VERSION 5.8 ;
BUSBITCHARS "[]" ;
DIVIDERCHAR "/" ;
UNITS
    DATABASE MICRONS 1000 ;
END UNITS

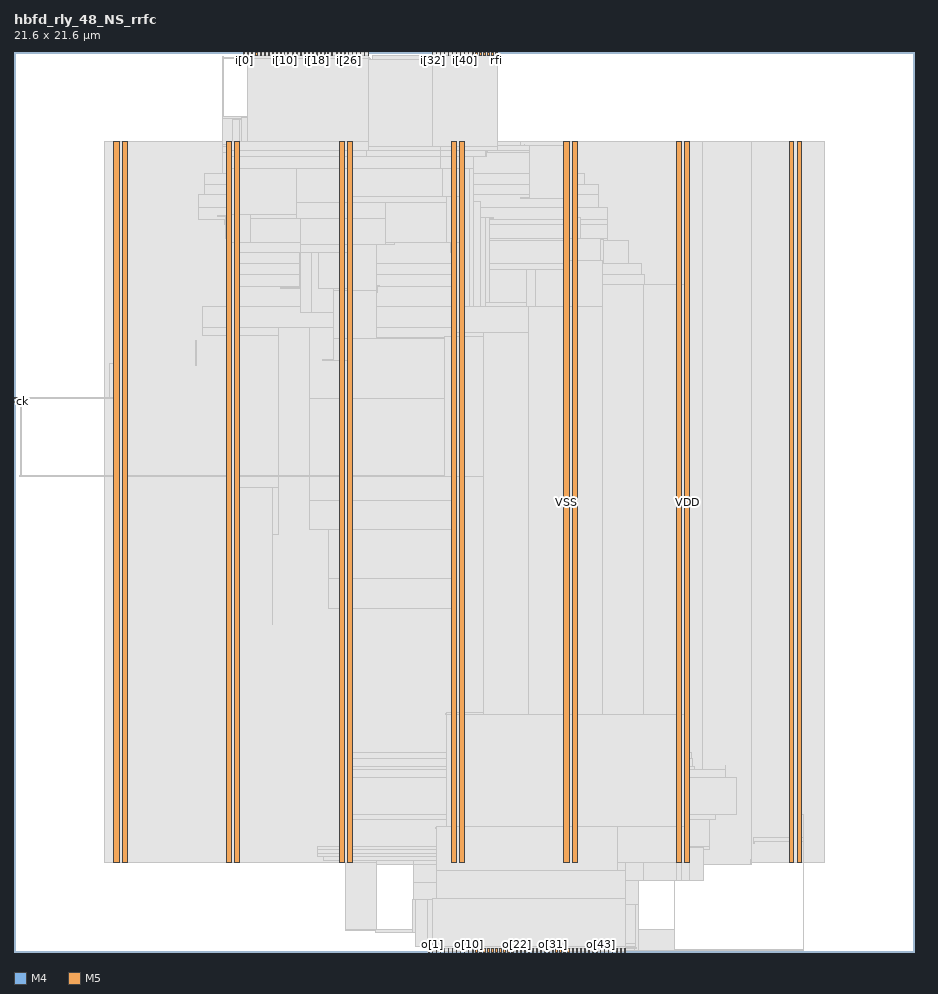
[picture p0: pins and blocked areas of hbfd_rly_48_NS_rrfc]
MACRO hbfd_rly_48_NS_rrfc
  FOREIGN hbfd_rly_48_NS_rrfc 0 0 ;
  CLASS BLOCK ;
  SIZE 21.6 BY 21.6 ;
  PIN ck
    DIRECTION INPUT ;
    USE SIGNAL ;
    PORT
      LAYER M4 ;
        RECT  0 13.2 0.084 13.224 ;
    END
  END ck
  PIN i[0]
    DIRECTION INPUT ;
    USE SIGNAL ;
    PORT
      LAYER M5 ;
        RECT  5.52 21.516 5.544 21.6 ;
    END
  END i[0]
  PIN i[10]
    DIRECTION INPUT ;
    USE SIGNAL ;
    PORT
      LAYER M5 ;
        RECT  6.48 21.516 6.504 21.6 ;
    END
  END i[10]
  PIN i[11]
    DIRECTION INPUT ;
    USE SIGNAL ;
    PORT
      LAYER M5 ;
        RECT  6.576 21.516 6.6 21.6 ;
    END
  END i[11]
  PIN i[12]
    DIRECTION INPUT ;
    USE SIGNAL ;
    PORT
      LAYER M5 ;
        RECT  6.672 21.516 6.696 21.6 ;
    END
  END i[12]
  PIN i[13]
    DIRECTION INPUT ;
    USE SIGNAL ;
    PORT
      LAYER M5 ;
        RECT  6.768 21.516 6.792 21.6 ;
    END
  END i[13]
  PIN i[14]
    DIRECTION INPUT ;
    USE SIGNAL ;
    PORT
      LAYER M5 ;
        RECT  6.864 21.516 6.888 21.6 ;
    END
  END i[14]
  PIN i[15]
    DIRECTION INPUT ;
    USE SIGNAL ;
    PORT
      LAYER M5 ;
        RECT  6.96 21.516 6.984 21.6 ;
    END
  END i[15]
  PIN i[16]
    DIRECTION INPUT ;
    USE SIGNAL ;
    PORT
      LAYER M5 ;
        RECT  7.056 21.516 7.08 21.6 ;
    END
  END i[16]
  PIN i[17]
    DIRECTION INPUT ;
    USE SIGNAL ;
    PORT
      LAYER M5 ;
        RECT  7.152 21.516 7.176 21.6 ;
    END
  END i[17]
  PIN i[18]
    DIRECTION INPUT ;
    USE SIGNAL ;
    PORT
      LAYER M5 ;
        RECT  7.248 21.516 7.272 21.6 ;
    END
  END i[18]
  PIN i[19]
    DIRECTION INPUT ;
    USE SIGNAL ;
    PORT
      LAYER M5 ;
        RECT  7.344 21.516 7.368 21.6 ;
    END
  END i[19]
  PIN i[1]
    DIRECTION INPUT ;
    USE SIGNAL ;
    PORT
      LAYER M5 ;
        RECT  5.616 21.516 5.64 21.6 ;
    END
  END i[1]
  PIN i[20]
    DIRECTION INPUT ;
    USE SIGNAL ;
    PORT
      LAYER M5 ;
        RECT  7.44 21.516 7.464 21.6 ;
    END
  END i[20]
  PIN i[21]
    DIRECTION INPUT ;
    USE SIGNAL ;
    PORT
      LAYER M5 ;
        RECT  7.536 21.516 7.56 21.6 ;
    END
  END i[21]
  PIN i[22]
    DIRECTION INPUT ;
    USE SIGNAL ;
    PORT
      LAYER M5 ;
        RECT  7.632 21.516 7.656 21.6 ;
    END
  END i[22]
  PIN i[23]
    DIRECTION INPUT ;
    USE SIGNAL ;
    PORT
      LAYER M5 ;
        RECT  7.728 21.516 7.752 21.6 ;
    END
  END i[23]
  PIN i[24]
    DIRECTION INPUT ;
    USE SIGNAL ;
    PORT
      LAYER M5 ;
        RECT  7.824 21.516 7.848 21.6 ;
    END
  END i[24]
  PIN i[25]
    DIRECTION INPUT ;
    USE SIGNAL ;
    PORT
      LAYER M5 ;
        RECT  7.92 21.516 7.944 21.6 ;
    END
  END i[25]
  PIN i[26]
    DIRECTION INPUT ;
    USE SIGNAL ;
    PORT
      LAYER M5 ;
        RECT  8.016 21.516 8.04 21.6 ;
    END
  END i[26]
  PIN i[27]
    DIRECTION INPUT ;
    USE SIGNAL ;
    PORT
      LAYER M5 ;
        RECT  8.112 21.516 8.136 21.6 ;
    END
  END i[27]
  PIN i[28]
    DIRECTION INPUT ;
    USE SIGNAL ;
    PORT
      LAYER M5 ;
        RECT  8.208 21.516 8.232 21.6 ;
    END
  END i[28]
  PIN i[29]
    DIRECTION INPUT ;
    USE SIGNAL ;
    PORT
      LAYER M5 ;
        RECT  8.304 21.516 8.328 21.6 ;
    END
  END i[29]
  PIN i[2]
    DIRECTION INPUT ;
    USE SIGNAL ;
    PORT
      LAYER M5 ;
        RECT  5.712 21.516 5.736 21.6 ;
    END
  END i[2]
  PIN i[30]
    DIRECTION INPUT ;
    USE SIGNAL ;
    PORT
      LAYER M5 ;
        RECT  8.4 21.516 8.424 21.6 ;
    END
  END i[30]
  PIN i[31]
    DIRECTION INPUT ;
    USE SIGNAL ;
    PORT
      LAYER M5 ;
        RECT  8.496 21.516 8.52 21.6 ;
    END
  END i[31]
  PIN i[32]
    DIRECTION INPUT ;
    USE SIGNAL ;
    PORT
      LAYER M5 ;
        RECT  10.032 21.516 10.056 21.6 ;
    END
  END i[32]
  PIN i[33]
    DIRECTION INPUT ;
    USE SIGNAL ;
    PORT
      LAYER M5 ;
        RECT  10.128 21.516 10.152 21.6 ;
    END
  END i[33]
  PIN i[34]
    DIRECTION INPUT ;
    USE SIGNAL ;
    PORT
      LAYER M5 ;
        RECT  10.224 21.516 10.248 21.6 ;
    END
  END i[34]
  PIN i[35]
    DIRECTION INPUT ;
    USE SIGNAL ;
    PORT
      LAYER M5 ;
        RECT  10.32 21.516 10.344 21.6 ;
    END
  END i[35]
  PIN i[36]
    DIRECTION INPUT ;
    USE SIGNAL ;
    PORT
      LAYER M5 ;
        RECT  10.416 21.516 10.44 21.6 ;
    END
  END i[36]
  PIN i[37]
    DIRECTION INPUT ;
    USE SIGNAL ;
    PORT
      LAYER M5 ;
        RECT  10.512 21.516 10.536 21.6 ;
    END
  END i[37]
  PIN i[38]
    DIRECTION INPUT ;
    USE SIGNAL ;
    PORT
      LAYER M5 ;
        RECT  10.608 21.516 10.632 21.6 ;
    END
  END i[38]
  PIN i[39]
    DIRECTION INPUT ;
    USE SIGNAL ;
    PORT
      LAYER M5 ;
        RECT  10.704 21.516 10.728 21.6 ;
    END
  END i[39]
  PIN i[3]
    DIRECTION INPUT ;
    USE SIGNAL ;
    PORT
      LAYER M5 ;
        RECT  5.808 21.516 5.832 21.6 ;
    END
  END i[3]
  PIN i[40]
    DIRECTION INPUT ;
    USE SIGNAL ;
    PORT
      LAYER M5 ;
        RECT  10.8 21.516 10.824 21.6 ;
    END
  END i[40]
  PIN i[41]
    DIRECTION INPUT ;
    USE SIGNAL ;
    PORT
      LAYER M5 ;
        RECT  10.896 21.516 10.92 21.6 ;
    END
  END i[41]
  PIN i[42]
    DIRECTION INPUT ;
    USE SIGNAL ;
    PORT
      LAYER M5 ;
        RECT  10.992 21.516 11.016 21.6 ;
    END
  END i[42]
  PIN i[43]
    DIRECTION INPUT ;
    USE SIGNAL ;
    PORT
      LAYER M5 ;
        RECT  11.088 21.516 11.112 21.6 ;
    END
  END i[43]
  PIN i[44]
    DIRECTION INPUT ;
    USE SIGNAL ;
    PORT
      LAYER M5 ;
        RECT  11.184 21.516 11.208 21.6 ;
    END
  END i[44]
  PIN i[45]
    DIRECTION INPUT ;
    USE SIGNAL ;
    PORT
      LAYER M5 ;
        RECT  11.28 21.516 11.304 21.6 ;
    END
  END i[45]
  PIN i[46]
    DIRECTION INPUT ;
    USE SIGNAL ;
    PORT
      LAYER M5 ;
        RECT  11.376 21.516 11.4 21.6 ;
    END
  END i[46]
  PIN i[47]
    DIRECTION INPUT ;
    USE SIGNAL ;
    PORT
      LAYER M5 ;
        RECT  11.472 21.516 11.496 21.6 ;
    END
  END i[47]
  PIN i[4]
    DIRECTION INPUT ;
    USE SIGNAL ;
    PORT
      LAYER M5 ;
        RECT  5.904 21.516 5.928 21.6 ;
    END
  END i[4]
  PIN i[5]
    DIRECTION INPUT ;
    USE SIGNAL ;
    PORT
      LAYER M5 ;
        RECT  6 21.516 6.024 21.6 ;
    END
  END i[5]
  PIN i[6]
    DIRECTION INPUT ;
    USE SIGNAL ;
    PORT
      LAYER M5 ;
        RECT  6.096 21.516 6.12 21.6 ;
    END
  END i[6]
  PIN i[7]
    DIRECTION INPUT ;
    USE SIGNAL ;
    PORT
      LAYER M5 ;
        RECT  6.192 21.516 6.216 21.6 ;
    END
  END i[7]
  PIN i[8]
    DIRECTION INPUT ;
    USE SIGNAL ;
    PORT
      LAYER M5 ;
        RECT  6.288 21.516 6.312 21.6 ;
    END
  END i[8]
  PIN i[9]
    DIRECTION INPUT ;
    USE SIGNAL ;
    PORT
      LAYER M5 ;
        RECT  6.384 21.516 6.408 21.6 ;
    END
  END i[9]
  PIN o[0]
    DIRECTION OUTPUT ;
    USE SIGNAL ;
    PORT
      LAYER M5 ;
        RECT  9.936 0 9.96 0.084 ;
    END
  END o[0]
  PIN o[10]
    DIRECTION OUTPUT ;
    USE SIGNAL ;
    PORT
      LAYER M5 ;
        RECT  10.896 0 10.92 0.084 ;
    END
  END o[10]
  PIN o[11]
    DIRECTION OUTPUT ;
    USE SIGNAL ;
    PORT
      LAYER M5 ;
        RECT  10.992 0 11.016 0.084 ;
    END
  END o[11]
  PIN o[12]
    DIRECTION OUTPUT ;
    USE SIGNAL ;
    PORT
      LAYER M5 ;
        RECT  11.088 0 11.112 0.084 ;
    END
  END o[12]
  PIN o[13]
    DIRECTION OUTPUT ;
    USE SIGNAL ;
    PORT
      LAYER M5 ;
        RECT  11.184 0 11.208 0.084 ;
    END
  END o[13]
  PIN o[14]
    DIRECTION OUTPUT ;
    USE SIGNAL ;
    PORT
      LAYER M5 ;
        RECT  11.28 0 11.304 0.084 ;
    END
  END o[14]
  PIN o[15]
    DIRECTION OUTPUT ;
    USE SIGNAL ;
    PORT
      LAYER M5 ;
        RECT  11.376 0 11.4 0.084 ;
    END
  END o[15]
  PIN o[16]
    DIRECTION OUTPUT ;
    USE SIGNAL ;
    PORT
      LAYER M5 ;
        RECT  11.472 0 11.496 0.084 ;
    END
  END o[16]
  PIN o[17]
    DIRECTION OUTPUT ;
    USE SIGNAL ;
    PORT
      LAYER M5 ;
        RECT  11.568 0 11.592 0.084 ;
    END
  END o[17]
  PIN o[18]
    DIRECTION OUTPUT ;
    USE SIGNAL ;
    PORT
      LAYER M5 ;
        RECT  11.664 0 11.688 0.084 ;
    END
  END o[18]
  PIN o[19]
    DIRECTION OUTPUT ;
    USE SIGNAL ;
    PORT
      LAYER M5 ;
        RECT  11.76 0 11.784 0.084 ;
    END
  END o[19]
  PIN o[1]
    DIRECTION OUTPUT ;
    USE SIGNAL ;
    PORT
      LAYER M5 ;
        RECT  10.032 0 10.056 0.084 ;
    END
  END o[1]
  PIN o[20]
    DIRECTION OUTPUT ;
    USE SIGNAL ;
    PORT
      LAYER M5 ;
        RECT  11.856 0 11.88 0.084 ;
    END
  END o[20]
  PIN o[21]
    DIRECTION OUTPUT ;
    USE SIGNAL ;
    PORT
      LAYER M5 ;
        RECT  11.952 0 11.976 0.084 ;
    END
  END o[21]
  PIN o[22]
    DIRECTION OUTPUT ;
    USE SIGNAL ;
    PORT
      LAYER M5 ;
        RECT  12.048 0 12.072 0.084 ;
    END
  END o[22]
  PIN o[23]
    DIRECTION OUTPUT ;
    USE SIGNAL ;
    PORT
      LAYER M5 ;
        RECT  12.144 0 12.168 0.084 ;
    END
  END o[23]
  PIN o[24]
    DIRECTION OUTPUT ;
    USE SIGNAL ;
    PORT
      LAYER M5 ;
        RECT  12.24 0 12.264 0.084 ;
    END
  END o[24]
  PIN o[25]
    DIRECTION OUTPUT ;
    USE SIGNAL ;
    PORT
      LAYER M5 ;
        RECT  12.336 0 12.36 0.084 ;
    END
  END o[25]
  PIN o[26]
    DIRECTION OUTPUT ;
    USE SIGNAL ;
    PORT
      LAYER M5 ;
        RECT  12.432 0 12.456 0.084 ;
    END
  END o[26]
  PIN o[27]
    DIRECTION OUTPUT ;
    USE SIGNAL ;
    PORT
      LAYER M5 ;
        RECT  12.528 0 12.552 0.084 ;
    END
  END o[27]
  PIN o[28]
    DIRECTION OUTPUT ;
    USE SIGNAL ;
    PORT
      LAYER M5 ;
        RECT  12.624 0 12.648 0.084 ;
    END
  END o[28]
  PIN o[29]
    DIRECTION OUTPUT ;
    USE SIGNAL ;
    PORT
      LAYER M5 ;
        RECT  12.72 0 12.744 0.084 ;
    END
  END o[29]
  PIN o[2]
    DIRECTION OUTPUT ;
    USE SIGNAL ;
    PORT
      LAYER M5 ;
        RECT  10.128 0 10.152 0.084 ;
    END
  END o[2]
  PIN o[30]
    DIRECTION OUTPUT ;
    USE SIGNAL ;
    PORT
      LAYER M5 ;
        RECT  12.816 0 12.84 0.084 ;
    END
  END o[30]
  PIN o[31]
    DIRECTION OUTPUT ;
    USE SIGNAL ;
    PORT
      LAYER M5 ;
        RECT  12.912 0 12.936 0.084 ;
    END
  END o[31]
  PIN o[32]
    DIRECTION OUTPUT ;
    USE SIGNAL ;
    PORT
      LAYER M5 ;
        RECT  13.008 0 13.032 0.084 ;
    END
  END o[32]
  PIN o[33]
    DIRECTION OUTPUT ;
    USE SIGNAL ;
    PORT
      LAYER M5 ;
        RECT  13.104 0 13.128 0.084 ;
    END
  END o[33]
  PIN o[34]
    DIRECTION OUTPUT ;
    USE SIGNAL ;
    PORT
      LAYER M5 ;
        RECT  13.2 0 13.224 0.084 ;
    END
  END o[34]
  PIN o[35]
    DIRECTION OUTPUT ;
    USE SIGNAL ;
    PORT
      LAYER M5 ;
        RECT  13.296 0 13.32 0.084 ;
    END
  END o[35]
  PIN o[36]
    DIRECTION OUTPUT ;
    USE SIGNAL ;
    PORT
      LAYER M5 ;
        RECT  13.392 0 13.416 0.084 ;
    END
  END o[36]
  PIN o[37]
    DIRECTION OUTPUT ;
    USE SIGNAL ;
    PORT
      LAYER M5 ;
        RECT  13.488 0 13.512 0.084 ;
    END
  END o[37]
  PIN o[38]
    DIRECTION OUTPUT ;
    USE SIGNAL ;
    PORT
      LAYER M5 ;
        RECT  13.584 0 13.608 0.084 ;
    END
  END o[38]
  PIN o[39]
    DIRECTION OUTPUT ;
    USE SIGNAL ;
    PORT
      LAYER M5 ;
        RECT  13.68 0 13.704 0.084 ;
    END
  END o[39]
  PIN o[3]
    DIRECTION OUTPUT ;
    USE SIGNAL ;
    PORT
      LAYER M5 ;
        RECT  10.224 0 10.248 0.084 ;
    END
  END o[3]
  PIN o[40]
    DIRECTION OUTPUT ;
    USE SIGNAL ;
    PORT
      LAYER M5 ;
        RECT  13.776 0 13.8 0.084 ;
    END
  END o[40]
  PIN o[41]
    DIRECTION OUTPUT ;
    USE SIGNAL ;
    PORT
      LAYER M5 ;
        RECT  13.872 0 13.896 0.084 ;
    END
  END o[41]
  PIN o[42]
    DIRECTION OUTPUT ;
    USE SIGNAL ;
    PORT
      LAYER M5 ;
        RECT  13.968 0 13.992 0.084 ;
    END
  END o[42]
  PIN o[43]
    DIRECTION OUTPUT ;
    USE SIGNAL ;
    PORT
      LAYER M5 ;
        RECT  14.064 0 14.088 0.084 ;
    END
  END o[43]
  PIN o[44]
    DIRECTION OUTPUT ;
    USE SIGNAL ;
    PORT
      LAYER M5 ;
        RECT  14.16 0 14.184 0.084 ;
    END
  END o[44]
  PIN o[45]
    DIRECTION OUTPUT ;
    USE SIGNAL ;
    PORT
      LAYER M5 ;
        RECT  14.256 0 14.28 0.084 ;
    END
  END o[45]
  PIN o[46]
    DIRECTION OUTPUT ;
    USE SIGNAL ;
    PORT
      LAYER M5 ;
        RECT  14.352 0 14.376 0.084 ;
    END
  END o[46]
  PIN o[47]
    DIRECTION OUTPUT ;
    USE SIGNAL ;
    PORT
      LAYER M5 ;
        RECT  14.448 0 14.472 0.084 ;
    END
  END o[47]
  PIN o[4]
    DIRECTION OUTPUT ;
    USE SIGNAL ;
    PORT
      LAYER M5 ;
        RECT  10.32 0 10.344 0.084 ;
    END
  END o[4]
  PIN o[5]
    DIRECTION OUTPUT ;
    USE SIGNAL ;
    PORT
      LAYER M5 ;
        RECT  10.416 0 10.44 0.084 ;
    END
  END o[5]
  PIN o[6]
    DIRECTION OUTPUT ;
    USE SIGNAL ;
    PORT
      LAYER M5 ;
        RECT  10.512 0 10.536 0.084 ;
    END
  END o[6]
  PIN o[7]
    DIRECTION OUTPUT ;
    USE SIGNAL ;
    PORT
      LAYER M5 ;
        RECT  10.608 0 10.632 0.084 ;
    END
  END o[7]
  PIN o[8]
    DIRECTION OUTPUT ;
    USE SIGNAL ;
    PORT
      LAYER M5 ;
        RECT  10.704 0 10.728 0.084 ;
    END
  END o[8]
  PIN o[9]
    DIRECTION OUTPUT ;
    USE SIGNAL ;
    PORT
      LAYER M5 ;
        RECT  10.8 0 10.824 0.084 ;
    END
  END o[9]
  PIN rfi
    DIRECTION INPUT ;
    USE SIGNAL ;
    PORT
      LAYER M5 ;
        RECT  11.568 21.516 11.592 21.6 ;
    END
  END rfi
  PIN rfo
    DIRECTION OUTPUT ;
    USE SIGNAL ;
    PORT
      LAYER M5 ;
        RECT  14.544 0 14.568 0.084 ;
    END
  END rfo
  PIN rs
    DIRECTION INPUT ;
    USE SIGNAL ;
    PORT
      LAYER M4 ;
        RECT  0 13.296 0.084 13.32 ;
    END
  END rs
  PIN rso
    DIRECTION OUTPUT ;
    USE SIGNAL ;
    PORT
      LAYER M5 ;
        RECT  14.64 0 14.664 0.084 ;
    END
  END rso
  PIN VDD
    DIRECTION INOUT ;
    USE POWER ;
    PORT
      LAYER M5 ;
        RECT  18.792 2.151 18.912 19.449 ;
        RECT  16.092 2.151 16.212 19.449 ;
        RECT  13.392 2.151 13.512 19.449 ;
        RECT  10.692 2.151 10.812 19.449 ;
        RECT  7.992 2.151 8.112 19.449 ;
        RECT  5.292 2.151 5.412 19.449 ;
        RECT  2.592 2.151 2.712 19.449 ;
    END
  END VDD
  PIN VSS
    DIRECTION INOUT ;
    USE GROUND ;
    PORT
      LAYER M5 ;
        RECT  18.6 2.137 18.72 19.463 ;
        RECT  15.9 2.137 16.02 19.463 ;
        RECT  13.2 2.137 13.32 19.463 ;
        RECT  10.5 2.137 10.62 19.463 ;
        RECT  7.8 2.137 7.92 19.463 ;
        RECT  5.1 2.137 5.22 19.463 ;
        RECT  2.4 2.137 2.52 19.463 ;
    END
  END VSS
  # OT_OBS_CLOSED layer=M5 d_um=1.536 added=18
  OBS
    LAYER RVTN ;
     RECT  2.16 2.16 19.44 2.295 ;
     RECT  2.16 2.565 19.44 2.835 ;
     RECT  2.16 3.105 19.44 3.375 ;
     RECT  2.16 3.645 19.44 3.915 ;
     RECT  2.16 4.185 19.44 4.455 ;
     RECT  2.16 4.725 19.44 4.995 ;
     RECT  2.16 5.265 19.44 5.535 ;
     RECT  2.16 5.805 19.44 6.075 ;
     RECT  2.16 6.345 19.44 6.615 ;
     RECT  2.16 6.885 19.44 7.155 ;
     RECT  2.16 7.425 19.44 7.695 ;
     RECT  2.16 7.965 19.44 8.235 ;
     RECT  2.16 8.505 19.44 8.775 ;
     RECT  2.16 9.045 19.44 9.315 ;
     RECT  2.16 9.585 19.44 9.855 ;
     RECT  2.16 10.125 19.44 10.395 ;
     RECT  2.16 10.665 19.44 10.935 ;
     RECT  2.16 11.205 19.44 11.475 ;
     RECT  2.16 11.745 19.44 12.015 ;
     RECT  2.16 12.285 19.44 12.555 ;
     RECT  2.16 12.825 19.44 13.095 ;
     RECT  2.16 13.365 19.44 13.635 ;
     RECT  2.16 13.905 19.44 14.175 ;
     RECT  2.16 14.445 19.44 14.715 ;
     RECT  2.16 14.985 19.44 15.255 ;
     RECT  2.16 15.525 19.44 15.795 ;
     RECT  2.16 16.065 19.44 16.335 ;
     RECT  2.16 16.605 19.44 16.875 ;
     RECT  2.16 17.145 19.44 17.415 ;
     RECT  2.16 17.685 19.44 17.955 ;
     RECT  2.16 18.225 19.44 18.495 ;
     RECT  2.16 18.765 19.44 19.035 ;
     RECT  2.16 19.305 19.44 19.44 ;
    LAYER RVTP ;
     RECT  2.16 2.295 19.44 2.565 ;
     RECT  2.16 2.835 19.44 3.105 ;
     RECT  2.16 3.375 19.44 3.645 ;
     RECT  2.16 3.915 19.44 4.185 ;
     RECT  2.16 4.455 19.44 4.725 ;
     RECT  2.16 4.995 19.44 5.265 ;
     RECT  2.16 5.535 19.44 5.805 ;
     RECT  2.16 6.075 19.44 6.345 ;
     RECT  2.16 6.615 19.44 6.885 ;
     RECT  2.16 7.155 19.44 7.425 ;
     RECT  2.16 7.695 19.44 7.965 ;
     RECT  2.16 8.235 19.44 8.505 ;
     RECT  2.16 8.775 19.44 9.045 ;
     RECT  2.16 9.315 19.44 9.585 ;
     RECT  2.16 9.855 19.44 10.125 ;
     RECT  2.16 10.395 19.44 10.665 ;
     RECT  2.16 10.935 19.44 11.205 ;
     RECT  2.16 11.475 19.44 11.745 ;
     RECT  2.16 12.015 19.44 12.285 ;
     RECT  2.16 12.555 19.44 12.825 ;
     RECT  2.16 13.095 19.44 13.365 ;
     RECT  2.16 13.635 19.44 13.905 ;
     RECT  2.16 14.175 19.44 14.445 ;
     RECT  2.16 14.715 19.44 14.985 ;
     RECT  2.16 15.255 19.44 15.525 ;
     RECT  2.16 15.795 19.44 16.065 ;
     RECT  2.16 16.335 19.44 16.605 ;
     RECT  2.16 16.875 19.44 17.145 ;
     RECT  2.16 17.415 19.44 17.685 ;
     RECT  2.16 17.955 19.44 18.225 ;
     RECT  2.16 18.495 19.44 18.765 ;
     RECT  2.16 19.035 19.44 19.305 ;
    LAYER M1 ;
     RECT  2.16 2.151 19.44 19.449 ;
    LAYER M2 ;
     RECT  2.16 2.151 8.599 19.449 ;
     RECT  8.599 2.106 9.671 19.449 ;
     RECT  9.671 2.151 11.119 19.449 ;
     RECT  11.119 2.106 12.155 19.449 ;
     RECT  13.027 0.531 13.207 0.549 ;
     RECT  13.207 0.036 14.899 0.549 ;
     RECT  14.899 0.036 14.999 1.17 ;
     RECT  14.999 0.036 15.863 0.549 ;
     RECT  12.155 2.151 16.519 19.449 ;
     RECT  16.519 2.106 17.699 19.449 ;
     RECT  15.863 0.036 18.959 0.054 ;
     RECT  17.699 2.151 19.44 19.449 ;
    LAYER M3 ;
     RECT  10.116 0.091 10.998 0.139 ;
     RECT  13.212 0.031 13.23 0.139 ;
     RECT  14.436 0.091 14.922 0.139 ;
     RECT  13.212 0.139 14.922 0.203 ;
     RECT  9.648 0.139 10.998 0.221 ;
     RECT  8.676 0.475 8.694 0.523 ;
     RECT  13.032 0.52 13.05 0.557 ;
     RECT  9.648 0.221 10.35 1.099 ;
     RECT  9.648 1.099 10.89 1.147 ;
     RECT  14.436 0.203 14.922 1.147 ;
     RECT  9.612 1.147 10.89 1.243 ;
     RECT  9.576 1.243 10.89 1.675 ;
     RECT  11.952 1.147 11.97 1.723 ;
     RECT  15.84 0.526 15.858 1.723 ;
     RECT  14.436 1.147 14.994 1.771 ;
     RECT  15.84 1.723 16.542 1.771 ;
     RECT  9.576 1.675 11.034 2.101 ;
     RECT  7.956 0.523 8.694 2.143 ;
     RECT  13.572 2.011 13.59 2.143 ;
     RECT  18.936 0.031 18.954 2.143 ;
     RECT  7.815 2.143 8.694 2.191 ;
     RECT  9.576 2.101 11.142 2.191 ;
     RECT  11.88 1.723 12.186 2.191 ;
     RECT  13.215 2.143 13.59 2.191 ;
     RECT  14.436 1.771 16.542 2.191 ;
     RECT  17.676 2.101 17.694 2.219 ;
     RECT  7.416 2.191 12.33 2.299 ;
     RECT  7.272 2.299 12.33 2.371 ;
     RECT  13.215 2.191 16.542 2.371 ;
     RECT  2.415 2.143 2.505 2.413 ;
     RECT  5.115 2.143 5.205 2.413 ;
     RECT  7.272 2.371 16.542 2.461 ;
     RECT  7.272 2.461 16.686 2.525 ;
     RECT  17.748 2.605 17.766 2.641 ;
     RECT  18.615 2.143 18.954 2.641 ;
     RECT  17.748 2.641 18.954 2.759 ;
     RECT  7.815 2.525 16.686 3.181 ;
     RECT  18.615 2.759 18.954 3.299 ;
     RECT  7.815 3.181 16.83 3.307 ;
     RECT  7.815 3.307 17.334 4.181 ;
     RECT  7.815 4.181 17.082 4.379 ;
     RECT  7.815 4.379 16.326 4.451 ;
     RECT  17.064 4.379 17.082 4.487 ;
     RECT  7.815 4.451 16.29 4.649 ;
     RECT  7.815 4.649 16.254 4.793 ;
     RECT  7.815 4.793 16.197 8.239 ;
     RECT  7.56 8.239 16.197 8.969 ;
     RECT  6.192 7.861 6.21 10.021 ;
     RECT  7.56 8.969 12.402 10.129 ;
     RECT  7.092 10.129 12.402 10.831 ;
     RECT  13.14 8.969 16.197 10.831 ;
     RECT  5.115 2.413 5.397 11.137 ;
     RECT  6.192 10.021 6.354 11.137 ;
     RECT  7.092 10.831 16.197 13.289 ;
     RECT  2.415 2.413 2.697 13.291 ;
     RECT  2.304 13.291 2.697 14.135 ;
     RECT  4.356 14.071 4.374 14.675 ;
     RECT  5.115 11.137 6.354 14.791 ;
     RECT  4.536 14.791 6.354 14.989 ;
     RECT  7.092 13.289 14.814 14.989 ;
     RECT  4.536 14.989 14.814 15.485 ;
     RECT  15.876 13.289 16.197 15.629 ;
     RECT  5.115 15.485 14.814 15.979 ;
     RECT  5.115 15.979 15.138 16.259 ;
     RECT  5.115 16.259 15.066 16.529 ;
     RECT  5.115 16.529 14.742 17.069 ;
     RECT  5.115 17.069 14.238 17.131 ;
     RECT  5.076 17.131 14.238 17.455 ;
     RECT  5.04 17.455 14.238 17.581 ;
     RECT  4.428 17.581 14.238 17.879 ;
     RECT  4.428 17.879 14.022 18.185 ;
     RECT  4.572 18.185 14.022 18.419 ;
     RECT  4.572 18.419 13.698 18.689 ;
     RECT  2.415 14.135 2.697 19.187 ;
     RECT  5.004 18.689 13.497 19.187 ;
     RECT  15.915 15.629 16.197 19.187 ;
     RECT  18.615 3.299 18.897 19.187 ;
     RECT  5.004 19.187 13.305 19.325 ;
     RECT  7.308 19.325 11.214 19.337 ;
     RECT  12.24 19.325 13.305 19.337 ;
     RECT  5.004 19.325 6.534 19.373 ;
     RECT  7.308 19.337 8.622 19.373 ;
     RECT  9.792 19.337 11.214 19.373 ;
     RECT  12.24 19.337 12.258 19.373 ;
     RECT  9.792 19.373 10.674 19.379 ;
     RECT  9.972 19.379 10.674 19.421 ;
     RECT  2.415 19.187 2.505 19.457 ;
     RECT  7.815 19.373 8.19 19.457 ;
     RECT  13.215 19.337 13.305 19.457 ;
     RECT  15.915 19.187 16.005 19.457 ;
     RECT  18.615 19.187 18.705 19.457 ;
     RECT  7.956 19.457 8.19 19.565 ;
     RECT  7.956 19.565 7.974 19.613 ;
     RECT  10.152 19.421 10.674 19.613 ;
     RECT  5.004 19.373 6.174 19.997 ;
     RECT  5.004 19.997 6.138 20.045 ;
     RECT  6.12 20.045 6.138 20.573 ;
     RECT  8.208 21.211 8.478 21.307 ;
     RECT  8.208 21.307 8.55 21.389 ;
     RECT  8.28 21.389 8.55 21.437 ;
     RECT  5.004 20.045 5.022 21.485 ;
     RECT  8.28 21.437 8.478 21.485 ;
    LAYER M4 ;
     RECT  0.084 13.2 0.179 13.224 ;
     RECT  0.06 13.224 0.179 13.296 ;
     RECT  0.084 13.296 0.179 13.32 ;
     RECT  0.133 11.424 2.408 11.448 ;
     RECT  0.179 13.296 2.408 13.32 ;
     RECT  2.408 2.148 2.512 19.452 ;
     RECT  2.512 2.418 2.704 19.182 ;
     RECT  4.885 17.664 5.065 17.688 ;
     RECT  2.704 11.424 5.108 11.448 ;
     RECT  5.065 17.136 5.108 17.688 ;
     RECT  5.108 2.148 5.212 19.452 ;
     RECT  5.212 2.418 5.245 19.452 ;
     RECT  5.245 2.418 5.404 19.992 ;
     RECT  5.404 18.816 5.461 19.992 ;
     RECT  4.993 21.456 5.555 21.48 ;
     RECT  5.404 17.04 5.699 17.688 ;
     RECT  5.461 18.816 6.035 20.04 ;
     RECT  6.035 19.2 6.109 20.04 ;
     RECT  6.109 19.2 6.323 20.568 ;
     RECT  6.323 20.544 6.419 20.568 ;
     RECT  5.699 17.04 6.716 17.16 ;
     RECT  6.397 15.936 6.853 15.96 ;
     RECT  6.716 17.04 6.853 17.64 ;
     RECT  6.853 15.936 6.865 17.64 ;
     RECT  6.323 19.2 7.004 19.368 ;
     RECT  6.865 15.36 7.141 17.64 ;
     RECT  7.004 18.816 7.141 19.368 ;
     RECT  7.405 14.208 7.669 14.232 ;
     RECT  7.141 15.36 7.669 19.368 ;
     RECT  7.573 21.408 7.669 21.432 ;
     RECT  5.404 11.424 7.808 11.448 ;
     RECT  7.669 14.208 7.808 19.368 ;
     RECT  7.808 2.148 7.901 19.452 ;
     RECT  7.901 2.148 7.912 19.608 ;
     RECT  7.912 2.418 7.985 19.608 ;
     RECT  7.669 21.312 8.101 21.432 ;
     RECT  7.985 2.418 8.104 19.56 ;
     RECT  8.104 14.64 8.129 14.76 ;
     RECT  8.101 21.264 8.197 21.432 ;
     RECT  8.104 15.84 8.201 19.56 ;
     RECT  8.197 21.216 8.242 21.432 ;
     RECT  8.242 21.216 8.489 21.48 ;
     RECT  8.489 21.312 8.531 21.48 ;
     RECT  8.201 15.84 8.561 19.368 ;
     RECT  8.531 21.312 8.561 21.432 ;
     RECT  8.561 21.312 8.572 21.336 ;
     RECT  8.561 19.344 8.633 19.368 ;
     RECT  7.945 0.528 8.665 0.552 ;
     RECT  8.561 15.84 8.669 18.36 ;
     RECT  8.669 15.84 8.723 16.008 ;
     RECT  8.723 15.984 8.777 16.008 ;
     RECT  8.669 16.992 9.137 18.36 ;
     RECT  8.665 0.48 9.565 0.552 ;
     RECT  9.565 0.48 9.637 1.272 ;
     RECT  9.137 17.088 9.709 18.36 ;
     RECT  9.709 17.088 9.781 18.456 ;
     RECT  9.637 0.144 9.925 1.272 ;
     RECT  9.781 17.088 9.961 19.368 ;
     RECT  9.961 17.088 10.141 19.416 ;
     RECT  10.141 17.088 10.357 19.608 ;
     RECT  10.261 21.36 10.357 21.384 ;
     RECT  9.925 0.096 10.465 1.272 ;
     RECT  10.105 2.976 10.465 3 ;
     RECT  10.357 17.04 10.465 19.608 ;
     RECT  10.465 0.096 10.508 3 ;
     RECT  10.357 5.712 10.508 5.736 ;
     RECT  8.104 11.424 10.508 11.448 ;
     RECT  8.129 14.736 10.508 14.76 ;
     RECT  10.465 16.8 10.508 19.608 ;
     RECT  10.508 0.096 10.685 19.608 ;
     RECT  10.357 21.36 10.739 21.432 ;
     RECT  10.685 0.096 10.804 19.368 ;
     RECT  10.739 21.36 10.835 21.384 ;
     RECT  10.804 14.736 10.937 19.368 ;
     RECT  10.937 14.832 11.027 19.368 ;
     RECT  11.027 14.832 11.189 18.024 ;
     RECT  11.189 14.832 11.305 17.64 ;
     RECT  11.027 19.104 11.333 19.368 ;
     RECT  11.333 19.2 11.369 19.368 ;
     RECT  11.305 15.6 11.405 17.64 ;
     RECT  10.804 4.992 11.513 5.688 ;
     RECT  11.405 17.616 11.513 17.64 ;
     RECT  10.804 2.688 11.621 2.808 ;
     RECT  10.804 0.096 11.869 1.704 ;
     RECT  11.869 0.096 12.197 1.752 ;
     RECT  12.085 13.152 12.301 13.176 ;
     RECT  11.405 15.6 12.301 16.392 ;
     RECT  11.621 2.784 12.325 2.808 ;
     RECT  12.325 2.784 12.373 3.24 ;
     RECT  12.157 18.096 12.373 18.12 ;
     RECT  11.369 19.248 12.373 19.368 ;
     RECT  12.197 0.096 12.467 1.272 ;
     RECT  12.373 2.784 12.469 3.768 ;
     RECT  12.301 15.456 12.517 16.392 ;
     RECT  12.467 0.096 12.563 1.176 ;
     RECT  12.469 2.784 12.581 3.864 ;
     RECT  11.513 4.992 12.581 5.256 ;
     RECT  12.581 2.784 12.709 5.256 ;
     RECT  12.709 2.784 12.901 5.304 ;
     RECT  12.409 6.288 12.901 6.312 ;
     RECT  12.901 2.784 12.949 6.312 ;
     RECT  12.301 13.104 12.949 13.176 ;
     RECT  12.563 0.096 13.061 0.552 ;
     RECT  12.949 2.256 13.208 6.312 ;
     RECT  12.553 7.44 13.208 7.464 ;
     RECT  12.949 12.528 13.208 13.176 ;
     RECT  12.517 15.408 13.208 16.392 ;
     RECT  12.373 18.096 13.208 19.368 ;
     RECT  13.208 2.148 13.312 19.452 ;
     RECT  13.312 2.148 13.429 19.182 ;
     RECT  13.429 1.728 13.504 19.182 ;
     RECT  13.504 16.56 13.601 17.64 ;
     RECT  13.061 0.096 13.619 0.408 ;
     RECT  13.504 15.408 13.645 15.432 ;
     RECT  13.619 0.096 13.667 0.312 ;
     RECT  13.504 13.152 13.667 13.176 ;
     RECT  13.504 11.088 13.681 11.112 ;
     RECT  13.504 1.728 14.141 5.688 ;
     RECT  13.601 16.56 14.141 17.112 ;
     RECT  14.141 16.56 14.149 16.584 ;
     RECT  13.667 0.096 14.501 0.264 ;
     RECT  14.141 3.936 14.537 5.688 ;
     RECT  14.537 3.936 14.681 5.16 ;
     RECT  14.501 0.096 14.933 0.12 ;
     RECT  14.141 1.728 15.109 2.856 ;
     RECT  14.681 3.936 15.109 3.96 ;
     RECT  15.109 1.728 15.908 3.96 ;
     RECT  14.681 5.136 15.908 5.16 ;
     RECT  15.109 15.984 15.908 16.008 ;
     RECT  15.908 1.728 16.012 19.452 ;
     RECT  16.012 1.728 16.204 19.182 ;
     RECT  16.204 1.728 16.553 2.52 ;
     RECT  18.608 2.148 18.712 19.452 ;
     RECT  18.712 2.418 18.904 19.182 ;
    LAYER M5 ;
     RECT  9.96 0.016 10.032 0.084 ;
     RECT  10.056 0.016 10.128 0.084 ;
     RECT  10.152 0.016 10.224 0.084 ;
     RECT  10.248 0.016 10.32 0.084 ;
     RECT  10.344 0.016 10.416 0.084 ;
     RECT  10.44 0.016 10.512 0.084 ;
     RECT  10.536 0.016 10.608 0.084 ;
     RECT  10.632 0.016 10.704 0.084 ;
     RECT  10.728 0.016 10.8 0.084 ;
     RECT  10.824 0.016 10.896 0.084 ;
     RECT  10.92 0.016 10.992 0.084 ;
     RECT  11.016 0.016 11.088 0.084 ;
     RECT  11.112 0.016 11.184 0.084 ;
     RECT  11.208 0.016 11.28 0.084 ;
     RECT  11.304 0.016 11.376 0.084 ;
     RECT  11.4 0.016 11.472 0.084 ;
     RECT  11.496 0.016 11.568 0.084 ;
     RECT  11.592 0.016 11.664 0.084 ;
     RECT  11.688 0.016 11.76 0.084 ;
     RECT  11.784 0.016 11.856 0.084 ;
     RECT  11.88 0.016 11.952 0.084 ;
     RECT  11.976 0.016 12.048 0.084 ;
     RECT  12.072 0.016 12.144 0.084 ;
     RECT  12.168 0.016 12.24 0.084 ;
     RECT  12.264 0.016 12.336 0.084 ;
     RECT  12.36 0.016 12.432 0.084 ;
     RECT  12.456 0.016 12.528 0.084 ;
     RECT  12.552 0.016 12.624 0.084 ;
     RECT  12.648 0.016 12.72 0.084 ;
     RECT  12.744 0.016 12.816 0.084 ;
     RECT  12.84 0.016 12.912 0.084 ;
     RECT  12.936 0.016 13.008 0.084 ;
     RECT  13.032 0.016 13.104 0.084 ;
     RECT  13.128 0.016 13.2 0.084 ;
     RECT  13.224 0.016 13.296 0.084 ;
     RECT  13.32 0.016 13.392 0.084 ;
     RECT  13.416 0.016 13.488 0.084 ;
     RECT  13.512 0.016 13.584 0.084 ;
     RECT  13.608 0.016 13.68 0.084 ;
     RECT  13.704 0.016 13.776 0.084 ;
     RECT  13.8 0.016 13.872 0.084 ;
     RECT  13.896 0.016 13.968 0.084 ;
     RECT  13.992 0.016 14.064 0.084 ;
     RECT  14.088 0.016 14.16 0.084 ;
     RECT  14.184 0.016 14.256 0.084 ;
     RECT  14.28 0.016 14.352 0.084 ;
     RECT  14.376 0.016 14.448 0.084 ;
     RECT  14.472 0.016 14.544 0.084 ;
     RECT  14.568 0.016 14.64 0.084 ;
     RECT  9.936 0.084 14.664 0.131 ;
     RECT  10.032 0.131 14.664 1.283 ;
     RECT  10.128 1.283 14.664 1.955 ;
     RECT  2.4 2.137 2.52 2.151 ;
     RECT  5.1 2.137 5.22 2.151 ;
     RECT  7.8 2.137 7.92 2.151 ;
     RECT  15.9 2.137 16.02 2.151 ;
     RECT  18.6 2.137 18.72 2.151 ;
     RECT  10.128 1.955 14.472 3.011 ;
     RECT  10.368 3.011 14.472 3.013 ;
     RECT  15.9 2.151 16.212 3.013 ;
     RECT  10.368 3.013 16.212 5.699 ;
     RECT  10.368 5.699 11.256 5.747 ;
     RECT  10.5 5.747 11.256 11.413 ;
     RECT  0.144 11.413 0.168 13.235 ;
     RECT  7.8 2.151 8.112 14.197 ;
     RECT  7.68 14.197 8.112 14.725 ;
     RECT  10.32 11.413 11.256 14.771 ;
     RECT  10.5 14.771 11.256 14.867 ;
     RECT  12.336 5.699 14.136 15.491 ;
     RECT  7.68 14.725 8.712 15.875 ;
     RECT  7.68 15.875 8.112 15.925 ;
     RECT  15.12 5.699 16.212 16.019 ;
     RECT  13.2 15.491 14.136 16.595 ;
     RECT  7.296 15.925 8.112 16.789 ;
     RECT  6.864 16.789 8.112 16.981 ;
     RECT  5.1 2.151 5.412 17.029 ;
     RECT  10.5 14.867 10.812 17.029 ;
     RECT  13.2 16.595 14.088 17.123 ;
     RECT  6.864 16.981 8.904 17.605 ;
     RECT  5.1 17.029 5.688 17.699 ;
     RECT  6.768 17.605 8.904 17.987 ;
     RECT  10.368 17.029 10.812 18.133 ;
     RECT  5.1 17.699 5.412 18.805 ;
     RECT  6.768 17.987 8.112 18.805 ;
     RECT  10.272 18.133 10.812 18.805 ;
     RECT  5.1 18.805 8.112 19.093 ;
     RECT  10.224 18.805 11.016 19.093 ;
     RECT  5.1 19.093 8.472 19.237 ;
     RECT  10.224 19.093 11.304 19.237 ;
     RECT  10.224 19.237 11.592 19.333 ;
     RECT  2.4 2.151 2.712 19.449 ;
     RECT  13.2 17.123 13.512 19.449 ;
     RECT  15.9 16.019 16.212 19.449 ;
     RECT  18.6 2.151 18.912 19.449 ;
     RECT  2.4 19.449 2.52 19.463 ;
     RECT  5.1 19.237 8.52 19.463 ;
     RECT  13.2 19.449 13.32 19.463 ;
     RECT  15.9 19.449 16.02 19.463 ;
     RECT  18.6 19.449 18.72 19.463 ;
     RECT  5.616 19.463 8.52 21.445 ;
     RECT  5.52 21.445 8.52 21.516 ;
     RECT  5.544 21.516 5.616 21.584 ;
     RECT  5.64 21.516 5.712 21.584 ;
     RECT  5.736 21.516 5.808 21.584 ;
     RECT  5.832 21.516 5.904 21.584 ;
     RECT  5.928 21.516 6 21.584 ;
     RECT  6.024 21.516 6.096 21.584 ;
     RECT  6.12 21.516 6.192 21.584 ;
     RECT  6.216 21.516 6.288 21.584 ;
     RECT  6.312 21.516 6.384 21.584 ;
     RECT  6.408 21.516 6.48 21.584 ;
     RECT  6.504 21.516 6.576 21.584 ;
     RECT  6.6 21.516 6.672 21.584 ;
     RECT  6.696 21.516 6.768 21.584 ;
     RECT  6.792 21.516 6.864 21.584 ;
     RECT  6.888 21.516 6.96 21.584 ;
     RECT  6.984 21.516 7.056 21.584 ;
     RECT  7.08 21.516 7.152 21.584 ;
     RECT  7.176 21.516 7.248 21.584 ;
     RECT  7.272 21.516 7.344 21.584 ;
     RECT  7.368 21.516 7.44 21.584 ;
     RECT  7.464 21.516 7.536 21.584 ;
     RECT  7.56 21.516 7.632 21.584 ;
     RECT  7.656 21.516 7.728 21.584 ;
     RECT  7.752 21.516 7.824 21.584 ;
     RECT  7.848 21.516 7.92 21.584 ;
     RECT  7.944 21.516 8.016 21.584 ;
     RECT  8.04 21.516 8.112 21.584 ;
     RECT  8.136 21.516 8.208 21.584 ;
     RECT  8.232 21.516 8.304 21.584 ;
     RECT  8.328 21.516 8.4 21.584 ;
     RECT  8.424 21.516 8.496 21.584 ;
     RECT  10.032 19.333 11.592 21.516 ;
     RECT  10.056 21.516 10.128 21.584 ;
     RECT  10.152 21.516 10.224 21.584 ;
     RECT  10.248 21.516 10.32 21.584 ;
     RECT  10.344 21.516 10.416 21.584 ;
     RECT  10.44 21.516 10.512 21.584 ;
     RECT  10.536 21.516 10.608 21.584 ;
     RECT  10.632 21.516 10.704 21.584 ;
     RECT  10.728 21.516 10.8 21.584 ;
     RECT  10.824 21.516 10.896 21.584 ;
     RECT  10.92 21.516 10.992 21.584 ;
     RECT  11.016 21.516 11.088 21.584 ;
     RECT  11.112 21.516 11.184 21.584 ;
     RECT  11.208 21.516 11.28 21.584 ;
     RECT  11.304 21.516 11.376 21.584 ;
     RECT  11.4 21.516 11.472 21.584 ;
     RECT  11.496 21.516 11.568 21.584 ;
     RECT  14.472 1.955 14.664 2.137 ;
     RECT  14.472 2.137 15.9 3.013 ;
     RECT  11.256 5.699 12.336 14.867 ;
     RECT  14.136 5.699 15.12 16.019 ;
     RECT  10.812 14.867 12.336 15.491 ;
     RECT  8.112 15.875 8.712 16.981 ;
     RECT  5.412 16.789 6.864 17.029 ;
     RECT  5.688 17.029 6.864 17.605 ;
     RECT  8.904 17.029 10.368 17.987 ;
     RECT  5.688 17.605 6.768 17.699 ;
     RECT  5.412 17.699 6.768 18.805 ;
     RECT  8.112 17.987 10.368 18.133 ;
     RECT  8.112 18.133 10.272 18.805 ;
     RECT  8.112 18.805 10.224 19.093 ;
     RECT  8.472 19.093 10.224 19.237 ;
     RECT  8.52 19.237 10.224 19.333 ;
     RECT  8.52 19.333 10.032 21.42 ;
     RECT  8.616 21.42 9.936 21.516 ;
  END
END hbfd_rly_48_NS_rrfc
END LIBRARY
